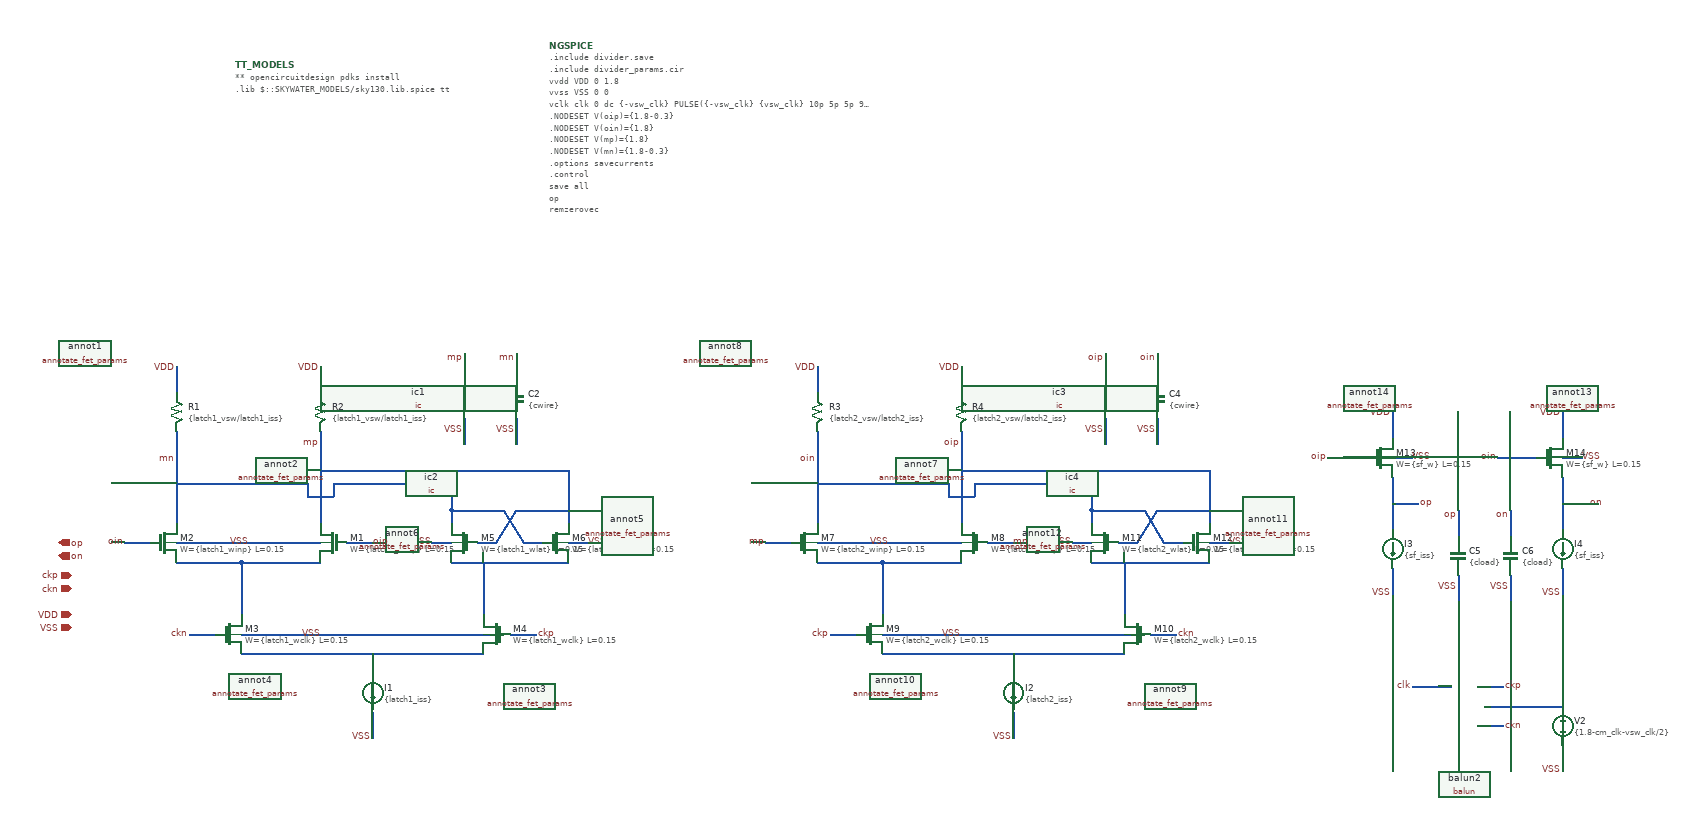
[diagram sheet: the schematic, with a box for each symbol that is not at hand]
v {xschem version=3.4.8RC file_version=1.3}
G {}
K {}
V {}
S {}
F {}
E {}
B 2 2110 -1020 3520 -650 {flags=graph
digital=0
y1=-0.5
y2=0.5
divy=5
x1=1.075e-09
x2=1.575e-09
ypos1=0
ypos2=0.5
divx=10
subdivx=1
dataset=0
unitx=1
 subdivy=1
legend=1
unity=1
color="7 21 4 12"
node="\\"ckp ckn -\\"
\\"op on -\\"
\\"mp mn -\\"
\\"oip oin -\\""
sim_type=tran
rawfile=$netlist_dir/divider.raw
logy=0
hilight_wave=-1
linewidth_mult=2
rainbow=0}
P 4 1 360 -400 {}
P 4 1 1340 -400 {}
N 460 -160 580 -160 {lab=#net1}
N 460 -160 460 -130 {lab=#net1}
N 580 -280 580 -220 {lab=mp}
N 620 -190 660 -190 {lab=oip}
N 360 -460 360 -420 {lab=VDD}
N 580 -460 580 -420 {lab=VDD}
N 660 70 660 110 {lab=VSS}
N 360 -160 460 -160 {lab=#net1}
N 360 -190 580 -190 {lab=VSS}
N 280 -190 320 -190 {lab=oin}
N 710 -20 830 -20 {lab=#net2}
N 660 -20 660 10 {lab=#net2}
N 870 -50 910 -50 {lab=ckp}
N 380 -50 420 -50 {lab=ckn}
N 460 -130 460 -80 {lab=#net1}
N 460 -50 830 -50 {lab=VSS}
N 460 -20 710 -20 {lab=#net2}
N 360 -360 360 -220 {lab=mn}
N 580 -360 580 -280 {lab=mp}
N 890 -190 920 -190 {lab=mn}
N 780 -240 780 -220 {lab=mn}
N 780 -270 780 -240 {lab=mn}
N 820 -190 850 -190 {lab=mp}
N 850 -190 880 -240 {lab=mp}
N 860 -240 890 -190 {lab=mn}
N 780 -240 860 -240 {lab=mn}
N 880 -240 960 -240 {lab=mp}
N 960 -280 960 -220 {lab=mp}
N 960 -300 960 -280 {lab=mp}
N 580 -300 960 -300 {lab=mp}
N 780 -280 780 -270 {lab=mn}
N 780 -160 960 -160 {lab=#net3}
N 830 -160 830 -80 {lab=#net3}
N 360 -280 540 -280 {lab=mn}
N 620 -280 780 -280 {lab=mn}
N 540 -280 560 -280 {lab=mn}
N 560 -280 560 -260 {lab=mn}
N 560 -260 600 -260 {lab=mn}
N 600 -280 600 -260 {lab=mn}
N 600 -280 620 -280 {lab=mn}
N 750 -190 780 -190 {lab=VSS}
N 960 -190 990 -190 {lab=VSS}
N 800 -480 800 -440 {lab=mp}
N 800 -380 800 -340 {lab=VSS}
N 880 -480 880 -440 {lab=mn}
N 880 -380 880 -340 {lab=VSS}
N 2350 90 2390 90 {lab=ckn}
N 2350 30 2390 30 {lab=ckp}
N 2250 30 2310 30 {lab=clk}
N 2360 60 2480 60 {lab=#net4}
N 2480 120 2480 160 {lab=VSS}
N 830 -50 840 -50 {lab=VSS}
N 1440 -160 1560 -160 {lab=#net5}
N 1440 -160 1440 -130 {lab=#net5}
N 1560 -280 1560 -220 {lab=oip}
N 1600 -190 1640 -190 {lab=mn}
N 1340 -460 1340 -420 {lab=VDD}
N 1560 -460 1560 -420 {lab=VDD}
N 1640 70 1640 110 {lab=VSS}
N 1340 -160 1440 -160 {lab=#net5}
N 1340 -190 1560 -190 {lab=VSS}
N 1260 -190 1300 -190 {lab=mp}
N 1690 -20 1810 -20 {lab=#net6}
N 1640 -20 1640 10 {lab=#net6}
N 1850 -50 1890 -50 {lab=ckn}
N 1360 -50 1400 -50 {lab=ckp}
N 1440 -130 1440 -80 {lab=#net5}
N 1440 -50 1810 -50 {lab=VSS}
N 1440 -20 1690 -20 {lab=#net6}
N 1340 -360 1340 -220 {lab=oin}
N 1560 -360 1560 -280 {lab=oip}
N 1870 -190 1900 -190 {lab=oin}
N 1760 -240 1760 -220 {lab=oin}
N 1760 -270 1760 -240 {lab=oin}
N 1800 -190 1830 -190 {lab=oip}
N 1830 -190 1860 -240 {lab=oip}
N 1840 -240 1870 -190 {lab=oin}
N 1760 -240 1840 -240 {lab=oin}
N 1860 -240 1940 -240 {lab=oip}
N 1940 -280 1940 -220 {lab=oip}
N 1940 -300 1940 -280 {lab=oip}
N 1560 -300 1940 -300 {lab=oip}
N 1760 -280 1760 -270 {lab=oin}
N 1760 -160 1940 -160 {lab=#net7}
N 1810 -160 1810 -80 {lab=#net7}
N 1340 -280 1520 -280 {lab=oin}
N 1600 -280 1760 -280 {lab=oin}
N 1520 -280 1540 -280 {lab=oin}
N 1540 -280 1540 -260 {lab=oin}
N 1540 -260 1580 -260 {lab=oin}
N 1580 -280 1580 -260 {lab=oin}
N 1580 -280 1600 -280 {lab=oin}
N 1730 -190 1760 -190 {lab=VSS}
N 1940 -190 1970 -190 {lab=VSS}
N 1780 -480 1780 -440 {lab=oip}
N 1780 -380 1780 -340 {lab=VSS}
N 1860 -480 1860 -440 {lab=oin}
N 1860 -380 1860 -340 {lab=VSS}
N 1810 -50 1820 -50 {lab=VSS}
N 2220 -150 2220 -110 {lab=VSS}
N 2220 -240 2220 -210 {lab=op}
N 2220 -290 2220 -240 {lab=op}
N 2220 -320 2250 -320 {lab=VSS}
N 2220 -390 2220 -350 {lab=VDD}
N 2220 -250 2260 -250 {lab=op}
N 2120 -320 2180 -320 {lab=oip}
N 2480 -150 2480 -110 {lab=VSS}
N 2480 -240 2480 -210 {lab=on}
N 2480 -290 2480 -240 {lab=on}
N 2480 -320 2510 -320 {lab=VSS}
N 2480 -390 2480 -350 {lab=VDD}
N 2480 -250 2520 -250 {lab=on}
N 2380 -320 2440 -320 {lab=oin}
N 2320 -240 2320 -200 {lab=op}
N 2320 -140 2320 -100 {lab=VSS}
N 2400 -240 2400 -200 {lab=on}
N 2400 -140 2400 -100 {lab=VSS}
C {devices/code.sym} 450 -920 0 0 {name=TT_MODELS
only_toplevel=true
format="tcleval( @value )"
value="
** opencircuitdesign pdks install
.lib $::SKYWATER_MODELS/sky130.lib.spice tt
"
spice_ignore=false}
C {sky130_fd_pr/nfet_01v8_lvt.sym} 340 -190 0 0 {name=M2
L=0.15
W=\{latch1_winp\}  
nf=\{latch1_nfinp\} mult=1
model=nfet_01v8_lvt
spiceprefix=X
}
C {sky130_fd_pr/nfet_01v8_lvt.sym} 600 -190 0 1 {name=M1
L=0.15
W=\{latch1_winp\}  
nf=\{latch1_nfinp\} mult=1
model=nfet_01v8_lvt
spiceprefix=X
}
C {iopin.sym} 200 -60 2 0 {name=p1 lab=VSS}
C {lab_wire.sym} 472.4345697278671 -190 0 0 {name=p2 lab=VSS
}
C {lab_pin.sym} 660 107.565430272133 3 0 {name=p3 lab=VSS}
C {isource.sym} 660 40 0 0 {name=I1 value=\{latch1_iss\}}
C {iopin.sym} 200 -80 2 0 {name=p4 lab=VDD}
C {lab_pin.sym} 360 -457.5654302721329 1 0 {name=p5 lab=VDD}
C {lab_pin.sym} 580 -457.5654302721329 1 0 {name=p6 lab=VDD}
C {opin.sym} 180 -190 0 0 {name=p14 lab=op}
C {opin.sym} 180 -170 0 0 {name=p15 lab=on}
C {devices/code_shown.sym} 930 -950 0 0 {name=NGSPICE
only_toplevel=true
value="
.include divider.save
.include divider_params.cir
vvdd VDD 0 1.8
vvss VSS 0 0
vclk clk 0 dc \{-vsw_clk\} PULSE(\{-vsw_clk\} \{vsw_clk\} 10p 5p 5p 95p 200p)
.NODESET V(oip)=\{1.8-0.3\}
.NODESET V(oin)=\{1.8\}
.NODESET V(mp)=\{1.8\}
.NODESET V(mn)=\{1.8-0.3\}
.options savecurrents
.control
save all
op
remzerovec 
write divider.raw
set appendwrite
tran 1p 2000p
let x = v(ckp)-v(ckn)
let y = v(oip)-v(oin)
meas tran tdiff TRIG x VAL=0 RISE=3 TARG y VAL=0 RISE=2
write divider.raw
.endc
" }
C {sky130_fd_pr/annotate_fet_params.sym} 580 -150 0 0 {name=annot2 ref=M1
W=136
nf=136}
C {sky130_fd_pr/annotate_fet_params.sym} 260 -130 0 0 {name=annot1 ref=M2}
C {devices/launcher.sym} 1830 -820 0 0 {name=h4 
descr="Load/unload
waveforms" 
tclcommand="
xschem raw_read $netlist_dir/divider.raw tran
"
}
C {devices/launcher.sym} 1830 -870 0 0 {name=h1
descr="Annotate OP" 
tclcommand="set show_hidden_texts 1; xschem annotate_op"
}
C {sky130_fd_pr/nfet_01v8_lvt.sym} 440 -50 0 0 {name=M3
L=0.15
W=\{latch1_wclk\}  
nf=\{latch1_nfclk\} mult=1
model=nfet_01v8_lvt
spiceprefix=X
}
C {sky130_fd_pr/nfet_01v8_lvt.sym} 850 -50 0 1 {name=M4
L=0.15
W=\{latch1_wclk\}  
nf=\{latch1_nfclk\} mult=1
model=nfet_01v8_lvt
spiceprefix=X
}
C {lab_wire.sym} 582.434569727867 -50 0 0 {name=p19 lab=VSS
}
C {sky130_fd_pr/nfet_01v8_lvt.sym} 800 -190 0 1 {name=M5
L=0.15
W=\{latch1_wlat\}
nf=\{latch1_nflat\}
mult=1
model=nfet_01v8_lvt
spiceprefix=X
}
C {sky130_fd_pr/nfet_01v8_lvt.sym} 940 -190 0 0 {name=M6
L=0.15
W=\{latch1_wlat\}  
nf=\{latch1_nflat\} mult=1
model=nfet_01v8_lvt
spiceprefix=X
}
C {lab_wire.sym} 752.434569727867 -190 0 0 {name=p24 lab=VSS}
C {lab_wire.sym} 987.565430272133 -190 0 1 {name=p25 lab=VSS
}
C {lab_pin.sym} 380 -50 0 0 {name=p20 lab=ckn}
C {lab_pin.sym} 910 -50 0 1 {name=p23 lab=ckp}
C {capa.sym} 800 -410 0 0 {name=C1
m=1
value=\{cwire\}
footprint=1206
device="ceramic capacitor"}
C {lab_wire.sym} 800 -362.434569727867 3 0 {name=p26 lab=VSS}
C {lab_wire.sym} 800 -472.434569727867 3 0 {name=p27 lab=mp}
C {capa.sym} 880 -410 0 0 {name=C2
m=1
value=\{cwire\}
footprint=1206
device="ceramic capacitor"}
C {lab_wire.sym} 880 -362.434569727867 3 0 {name=p28 lab=VSS}
C {lab_wire.sym} 880 -472.434569727867 3 0 {name=p29 lab=mn}
C {ipin.sym} 200 -140 0 0 {name=p30 lab=ckp}
C {ipin.sym} 200 -120 0 0 {name=p31 lab=ckn}
C {/foss/designs/balun/balun.sym} 2330 60 0 0 {name=balun2}
C {lab_pin.sym} 2390 90 0 1 {name=p32 lab=ckn}
C {lab_pin.sym} 2390 30 0 1 {name=p33 lab=ckp}
C {lab_pin.sym} 2250 30 0 0 {name=p34 lab=clk}
C {vsource.sym} 2480 90 0 0 {name=V2 value=\{1.8-cm_clk-vsw_clk/2\} savecurrent=true}
C {lab_pin.sym} 2480 157.565430272133 3 0 {name=p36 lab=VSS}
C {sky130_fd_pr/annotate_fet_params.sym} 760 20 0 0 {name=annot3 ref=M4}
C {sky130_fd_pr/annotate_fet_params.sym} 480 30 0 0 {name=annot4 ref=M3}
C {sky130_fd_pr/annotate_fet_params.sym} 1010 -130 0 0 {name=annot5 ref=M6}
C {sky130_fd_pr/annotate_fet_params.sym} 710 -140 0 0 {name=annot6 ref=M5}
C {ic.sym} 750 -300 0 0 {name=ic1 value=\{1.8-0.3\}}
C {ic.sym} 750 -280 2 1 {name=ic2 value=\{1.8\}}
C {sky130_fd_pr/nfet_01v8_lvt.sym} 1320 -190 0 0 {name=M7
L=0.15
W=\{latch2_winp\}  
nf=\{latch2_nfinp\} mult=1
model=nfet_01v8_lvt
spiceprefix=X
}
C {sky130_fd_pr/nfet_01v8_lvt.sym} 1580 -190 0 1 {name=M8
L=0.15
W=\{latch2_winp\}  
nf=\{latch2_nfinp\} mult=1
model=nfet_01v8_lvt
spiceprefix=X
}
C {lab_wire.sym} 1452.434569727867 -190 0 0 {name=p21 lab=VSS
}
C {lab_pin.sym} 1640 107.565430272133 3 0 {name=p35 lab=VSS}
C {isource.sym} 1640 40 0 0 {name=I2 value=\{latch2_iss\}}
C {lab_pin.sym} 1340 -457.5654302721329 1 0 {name=p37 lab=VDD}
C {lab_pin.sym} 1560 -457.5654302721329 1 0 {name=p38 lab=VDD}
C {lab_pin.sym} 2260 -250 2 0 {name=p43 lab=op}
C {sky130_fd_pr/annotate_fet_params.sym} 1560 -150 0 0 {name=annot7 ref=M8}
C {sky130_fd_pr/annotate_fet_params.sym} 1240 -130 0 0 {name=annot8 ref=M7}
C {sky130_fd_pr/nfet_01v8_lvt.sym} 1420 -50 0 0 {name=M9
L=0.15
W=\{latch2_wclk\}  
nf=\{latch2_nfclk\} mult=1
model=nfet_01v8_lvt
spiceprefix=X
}
C {sky130_fd_pr/nfet_01v8_lvt.sym} 1830 -50 0 1 {name=M10
L=0.15
W=\{latch2_wclk\}  
nf=\{latch2_nfclk\} mult=1
model=nfet_01v8_lvt
spiceprefix=X
}
C {lab_wire.sym} 1562.434569727867 -50 0 0 {name=p44 lab=VSS
}
C {sky130_fd_pr/nfet_01v8_lvt.sym} 1780 -190 0 1 {name=M11
L=0.15
W=\{latch2_wlat\}
nf=\{latch2_nflat\}
mult=1
model=nfet_01v8_lvt
spiceprefix=X
}
C {sky130_fd_pr/nfet_01v8_lvt.sym} 1920 -190 0 0 {name=M12
L=0.15
W=\{latch2_wlat\}  
nf=\{latch2_nflat\} mult=1
model=nfet_01v8_lvt
spiceprefix=X
}
C {lab_wire.sym} 1732.434569727867 -190 0 0 {name=p45 lab=VSS}
C {lab_wire.sym} 1967.565430272133 -190 0 1 {name=p46 lab=VSS
}
C {lab_pin.sym} 1360 -50 0 0 {name=p47 lab=ckp
}
C {lab_pin.sym} 1890 -50 0 1 {name=p48 lab=ckn
}
C {capa.sym} 1780 -410 0 0 {name=C3
m=1
value=\{cwire\}
footprint=1206
device="ceramic capacitor"}
C {lab_wire.sym} 1780 -362.434569727867 3 0 {name=p49 lab=VSS}
C {lab_wire.sym} 1780 -472.434569727867 3 0 {name=p50 lab=oip}
C {capa.sym} 1860 -410 0 0 {name=C4
m=1
value=\{cwire\}
footprint=1206
device="ceramic capacitor"}
C {lab_wire.sym} 1860 -362.434569727867 3 0 {name=p51 lab=VSS}
C {lab_wire.sym} 1860 -472.434569727867 3 0 {name=p52 lab=oin}
C {sky130_fd_pr/annotate_fet_params.sym} 1740 20 0 0 {name=annot9 ref=M10}
C {sky130_fd_pr/annotate_fet_params.sym} 1460 30 0 0 {name=annot10 ref=M9}
C {sky130_fd_pr/annotate_fet_params.sym} 1990 -130 0 0 {name=annot11 ref=M12}
C {sky130_fd_pr/annotate_fet_params.sym} 1690 -140 0 0 {name=annot12 ref=M11}
C {ic.sym} 1730 -300 0 0 {name=ic3 value=\{1.8-0.3\}}
C {ic.sym} 1730 -280 2 1 {name=ic4 value=\{1.8\}}
C {lab_wire.sym} 360 -317.565430272133 1 0 {name=p8 lab=mn}
C {lab_wire.sym} 580 -342.434569727867 3 0 {name=p9 lab=mp}
C {lab_wire.sym} 282.4345697278671 -190 0 0 {name=p10 lab=oin
W=136
nf=136}
C {lab_wire.sym} 657.565430272133 -190 0 1 {name=p11 lab=oip}
C {lab_wire.sym} 1340 -317.565430272133 1 0 {name=p40 lab=oin}
C {lab_wire.sym} 1560 -342.434569727867 3 0 {name=p41 lab=oip}
C {lab_wire.sym} 1262.434569727867 -190 0 0 {name=p53 lab=mp
W=136
nf=136}
C {lab_wire.sym} 1637.565430272133 -190 0 1 {name=p54 lab=mn}
C {sky130_fd_pr/nfet_01v8_lvt.sym} 2200 -320 0 0 {name=M13
L=0.15
W=\{sf_w\}
nf=\{sf_nf\}
mult=1
model=nfet_01v8_lvt
spiceprefix=X
}
C {lab_pin.sym} 2220 -112.434569727867 3 0 {name=p55 lab=VSS}
C {isource.sym} 2220 -180 0 0 {name=I3 value=\{sf_iss\}
}
C {lab_wire.sym} 2247.565430272133 -320 0 1 {name=p56 lab=VSS
}
C {lab_pin.sym} 2220 -387.5654302721329 1 0 {name=p57 lab=VDD}
C {lab_wire.sym} 2122.434569727867 -320 0 0 {name=p58 lab=oip}
C {lab_pin.sym} 2520 -250 2 0 {name=p59 lab=on}
C {lab_pin.sym} 2480 -112.434569727867 3 0 {name=p60 lab=VSS}
C {isource.sym} 2480 -180 0 0 {name=I4 value=\{sf_iss\}
}
C {lab_wire.sym} 2507.565430272133 -320 0 1 {name=p61 lab=VSS
}
C {lab_pin.sym} 2480 -387.5654302721329 1 0 {name=p62 lab=VDD}
C {lab_wire.sym} 2382.434569727867 -320 0 0 {name=p63 lab=oin}
C {capa.sym} 2320 -170 0 0 {name=C5
m=1
value=\{cload\}
footprint=1206
device="ceramic capacitor"}
C {lab_wire.sym} 2320 -122.434569727867 3 0 {name=p12 lab=VSS}
C {lab_wire.sym} 2320 -232.434569727867 3 0 {name=p13 lab=op}
C {capa.sym} 2400 -170 0 0 {name=C6
m=1
value=\{cload\}
footprint=1206
device="ceramic capacitor"}
C {lab_wire.sym} 2400 -122.434569727867 3 0 {name=p16 lab=VSS}
C {lab_wire.sym} 2400 -232.434569727867 3 0 {name=p17 lab=on}
C {res.sym} 360 -390 0 0 {name=R1
value=\{latch1_vsw/latch1_iss\}
footprint=1206
device=resistor
m=1}
C {res.sym} 580 -390 0 0 {name=R2
value=\{latch1_vsw/latch1_iss\}
footprint=1206
device=resistor
m=1}
C {res.sym} 1340 -390 0 0 {name=R3
value=\{latch2_vsw/latch2_iss\}
footprint=1206
device=resistor
m=1}
C {res.sym} 1560 -390 0 0 {name=R4
value=\{latch2_vsw/latch2_iss\}
footprint=1206
device=resistor
m=1}
C {sky130_fd_pr/nfet_01v8_lvt.sym} 2460 -320 0 0 {name=M14
L=0.15
W=\{sf_w\}
nf=\{sf_nf\}
mult=1
model=nfet_01v8_lvt
spiceprefix=X
}
C {sky130_fd_pr/annotate_fet_params.sym} 2540 -460 0 0 {name=annot13 ref=M14}
C {sky130_fd_pr/annotate_fet_params.sym} 2240 -470 0 0 {name=annot14 ref=M13}
